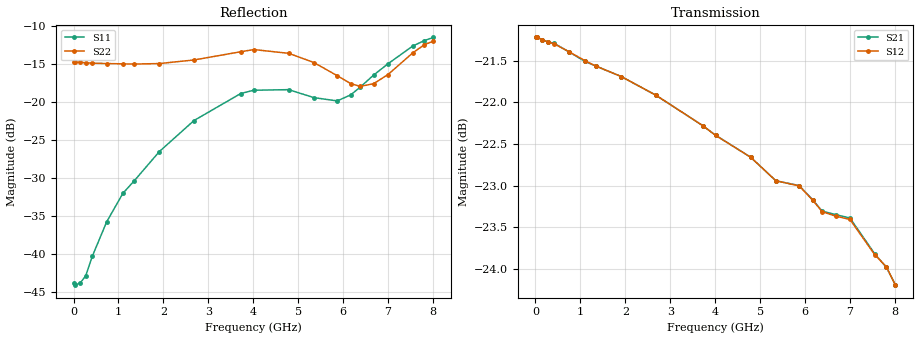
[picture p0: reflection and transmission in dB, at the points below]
! DEVICE ID: PE43712
! File Path: z:\PE43713\PE43713_CHAR_NOM_04292014\AMB\3p300\LS_ATT_20p00dB\PE43713_AMB_3p300V_3p000V_0p000V_LS_ATT_20p00dB_S2P_SN_10_A0139A.s2p
! Serial: 10
! Lot: A0139A
! Temp: 25C
! VDD: 3.300
! VSS: 0.000
! Control_Hi: 3.000
! Control_Lo: 0.000
! Attenuation Step: 20.00dB
! Port 1: RF1
! Port 2: RF2
! ThroughPath:1-2
! IDD: 0.0001466469
! ISS: -9.96e-008
#  Hz  S  RI  R  50
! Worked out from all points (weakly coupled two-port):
!   801 points, 10 MHz to 8.01 GHz, reference 50 ohm
!   highest |S21| = -21.22 dB at 10 MHz (marker M1); lowest = -24.2 dB at 8.01 GHz (marker M2)
!   lowest |S11| = -44.1 dB at 30 MHz (marker M3), VSWR 1.01, Z = 49.4 + j0.137 ohm
!   |S11| at or under -10 dB: start of sweep to end of sweep
!   |S22| runs from -18.0 to -12.0 dB; largest |S21 - S12| = 0.00031
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1e7  -0.00643 0.000556  0.0869 -0.000404  0.0869 -0.000388  -0.1844 0.00115
3e7  -0.00605 0.00139  0.0869 -0.00109  0.0869 -0.00109  -0.1838 0.00295
1.5e8  -0.00522 0.00374  0.0865 -0.00509  0.0865 -0.00509  -0.1822 0.011
2.7e8  -0.00453 0.0055  0.0859 -0.00895  0.0859 -0.00899  -0.1806 0.0175
4.2e8  -0.00419 0.00869  0.0851 -0.0137  0.085 -0.0138  -0.1785 0.0258
7.4e8  -0.00385 0.0158  0.082 -0.0231  0.082 -0.0232  -0.1735 0.0452
1.1e9  -0.00246 0.0249  0.0774 -0.0328  0.0775 -0.0328  -0.166 0.0655
1.35e9  -1.24e-05 0.0302  0.0739 -0.0389  0.0739 -0.0389  -0.16 0.0777
1.91e9  0.00872 0.0463  0.0643 -0.0514  0.0643 -0.0514  -0.1415 0.11
2.68e9  0.0268 0.0705  0.0477 -0.0645  0.0477 -0.0645  -0.1097 0.1542
3.72e9  0.0388 0.1068  0.0217 -0.0738  0.0217 -0.0738  -0.0837 0.1973
4.01e9  0.0401 0.1126  0.0145 -0.0745  0.0144 -0.0745  -0.0824 0.2058
4.79e9  0.0438 0.1124  -0.0042 -0.0735  -0.00422 -0.0735  -0.0679 0.198
5.35e9  0.0562 0.0909  -0.0162 -0.0694  -0.0162 -0.0694  -0.0515 0.1747
5.87e9  0.0769 0.0665  -0.0271 -0.0654  -0.027 -0.0654  -0.014 0.1484
6.17e9  0.0952 0.0579  -0.0335 -0.0608  -0.0334 -0.0608  0.0157 0.1313
6.38e9  0.1123 0.0555  -0.0363 -0.0579  -0.0362 -0.0579  0.04 0.1202
6.68e9  0.1412 0.052  -0.0412 -0.0541  -0.0411 -0.054  0.077 0.1072
7e9  0.1705 0.0535  -0.0468 -0.0489  -0.0467 -0.0488  0.1117 0.1027
7.55e9  0.2252 0.0625  -0.0528 -0.0369  -0.0527 -0.0369  0.1778 0.1131
7.81e9  0.2442 0.07  -0.0544 -0.0322  -0.0544 -0.0323  0.2052 0.1218
8.01e9  0.2555 0.0763  -0.0548 -0.0284  -0.0547 -0.0285  0.2186 0.1253
